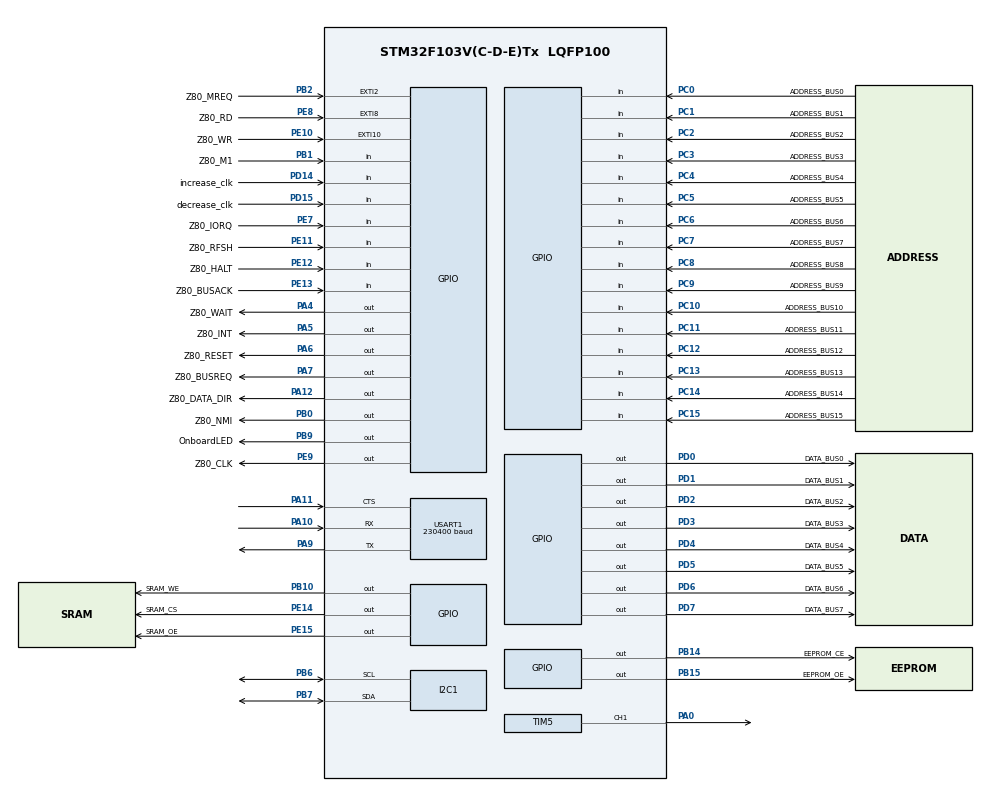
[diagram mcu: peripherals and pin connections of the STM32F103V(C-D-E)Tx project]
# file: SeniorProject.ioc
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Mcu.Family=STM32F1
Mcu.Name=STM32F103V(C-D-E)Tx
Mcu.Package=LQFP100
NVIC.EXTI15_10_IRQn=true\:0\:0\:false\:false\:true\:true
NVIC.EXTI2_IRQn=true\:0\:0\:false\:false\:true\:true
NVIC.EXTI9_5_IRQn=true\:0\:0\:false\:false\:true\:true
NVIC.PriorityGroup=NVIC_PRIORITYGROUP_4
PA0-WKUP.Signal=S_TIM5_CH1
PA10.Mode=Asynchronous
PA10.Signal=USART1_RX
PA11.Mode=CTS_Only
PA11.Signal=USART1_CTS
PA12.GPIO_Label=Z80_DATA_DIR
PA12.GPIO_Speed=GPIO_SPEED_FREQ_MEDIUM
PA12.PinState=GPIO_PIN_RESET
PA12.Signal=GPIO_Output
PA13.Mode=Serial_Wire
PA13.Signal=SYS_JTMS-SWDIO
PA14.Mode=Serial_Wire
PA14.Signal=SYS_JTCK-SWCLK
PA4.GPIO_Label=Z80_WAIT
PA4.GPIO_Speed=GPIO_SPEED_FREQ_MEDIUM
PA4.PinState=GPIO_PIN_SET
PA4.Signal=GPIO_Output
PA5.GPIO_Label=Z80_INT
PA5.GPIO_Speed=GPIO_SPEED_FREQ_MEDIUM
PA5.PinState=GPIO_PIN_SET
PA5.Signal=GPIO_Output
PA6.GPIO_Label=Z80_RESET
PA6.GPIO_Speed=GPIO_SPEED_FREQ_MEDIUM
PA6.PinState=GPIO_PIN_RESET
PA6.Signal=GPIO_Output
PA7.GPIO_Label=Z80_BUSREQ
PA7.GPIO_Speed=GPIO_SPEED_FREQ_MEDIUM
PA7.PinState=GPIO_PIN_SET
PA7.Signal=GPIO_Output
PA9.Mode=Asynchronous
PA9.Signal=USART1_TX
PB0.GPIO_Label=Z80_NMI
PB0.GPIO_Speed=GPIO_SPEED_FREQ_MEDIUM
PB0.Signal=GPIO_Output
PB1.GPIO_Label=Z80_M1
PB1.Signal=GPIO_Input
PB10.GPIO_Label=SRAM_WE
PB10.GPIO_Speed=GPIO_SPEED_FREQ_MEDIUM
PB10.PinState=GPIO_PIN_SET
PB10.Signal=GPIO_Output
PB14.GPIO_Label=EEPROM_CE
PB14.GPIO_Speed=GPIO_SPEED_FREQ_MEDIUM
PB14.PinState=GPIO_PIN_SET
PB14.Signal=GPIO_Output
PB15.GPIO_Label=EEPROM_OE
PB15.GPIO_Speed=GPIO_SPEED_FREQ_MEDIUM
PB15.PinState=GPIO_PIN_SET
PB15.Signal=GPIO_Output
PB2.GPIO_Label=Z80_MREQ
PB2.GPIO_ModeDefaultEXTI=GPIO_MODE_IT_FALLING
PB2.Signal=GPXTI2
PB6.Mode=I2C
PB6.Signal=I2C1_SCL
PB7.Mode=I2C
PB7.Signal=I2C1_SDA
PB9.GPIO_Label=OnboardLED
PB9.GPIO_ModeDefaultOutputPP=GPIO_MODE_OUTPUT_PP
PB9.PinState=GPIO_PIN_SET
PB9.Signal=GPIO_Output
PC0.GPIO_Label=ADDRESS_BUS0
PC0.Signal=GPIO_Input
PC1.GPIO_Label=ADDRESS_BUS1
PC1.Signal=GPIO_Input
PC10.GPIO_Label=ADDRESS_BUS10
PC10.Signal=GPIO_Input
PC11.GPIO_Label=ADDRESS_BUS11
PC11.Signal=GPIO_Input
PC12.GPIO_Label=ADDRESS_BUS12
PC12.Signal=GPIO_Input
PC13-TAMPER-RTC.GPIO_Label=ADDRESS_BUS13
PC13-TAMPER-RTC.Signal=GPIO_Input
PC14-OSC32_IN.GPIO_Label=ADDRESS_BUS14
PC14-OSC32_IN.Signal=GPIO_Input
PC15-OSC32_OUT.GPIO_Label=ADDRESS_BUS15
PC15-OSC32_OUT.Signal=GPIO_Input
PC2.GPIO_Label=ADDRESS_BUS2
PC2.Signal=GPIO_Input
PC3.GPIO_Label=ADDRESS_BUS3
PC3.Signal=GPIO_Input
PC4.GPIO_Label=ADDRESS_BUS4
PC4.Signal=GPIO_Input
PC5.GPIO_Label=ADDRESS_BUS5
PC5.Signal=GPIO_Input
PC6.GPIO_Label=ADDRESS_BUS6
PC6.Signal=GPIO_Input
PC7.GPIO_Label=ADDRESS_BUS7
PC7.Signal=GPIO_Input
PC8.GPIO_Label=ADDRESS_BUS8
PC8.Signal=GPIO_Input
PC9.GPIO_Label=ADDRESS_BUS9
PC9.Signal=GPIO_Input
PD0.GPIO_Label=DATA_BUS0
PD0.GPIO_Speed=GPIO_SPEED_FREQ_MEDIUM
PD0.Signal=GPIO_Output
PD1.GPIO_Label=DATA_BUS1
PD1.GPIO_Speed=GPIO_SPEED_FREQ_MEDIUM
PD1.Signal=GPIO_Output
PD14.GPIO_Label=increase_clk
PD14.Signal=GPIO_Input
PD15.GPIO_Label=decrease_clk
PD15.Signal=GPIO_Input
PD2.GPIO_Label=DATA_BUS2
PD2.GPIO_Speed=GPIO_SPEED_FREQ_MEDIUM
PD2.Signal=GPIO_Output
PD3.GPIO_Label=DATA_BUS3
PD3.GPIO_Speed=GPIO_SPEED_FREQ_MEDIUM
PD3.Signal=GPIO_Output
PD4.GPIO_Label=DATA_BUS4
PD4.GPIO_Speed=GPIO_SPEED_FREQ_MEDIUM
PD4.Signal=GPIO_Output
PD5.GPIO_Label=DATA_BUS5
PD5.GPIO_Speed=GPIO_SPEED_FREQ_MEDIUM
PD5.Signal=GPIO_Output
PD6.GPIO_Label=DATA_BUS6
PD6.GPIO_Speed=GPIO_SPEED_FREQ_MEDIUM
PD6.Signal=GPIO_Output
PD7.GPIO_Label=DATA_BUS7
PD7.GPIO_Speed=GPIO_SPEED_FREQ_MEDIUM
PD7.Signal=GPIO_Output
PE10.GPIO_Label=Z80_WR
PE10.GPIO_ModeDefaultEXTI=GPIO_MODE_IT_FALLING
PE10.Signal=GPXTI10
PE11.GPIO_Label=Z80_RFSH
PE11.Signal=GPIO_Input
PE12.GPIO_Label=Z80_HALT
PE12.Signal=GPIO_Input
PE13.GPIO_Label=Z80_BUSACK
PE13.Signal=GPIO_Input
PE14.GPIO_Label=SRAM_CS
PE14.GPIO_Speed=GPIO_SPEED_FREQ_MEDIUM
PE14.PinState=GPIO_PIN_SET
PE14.Signal=GPIO_Output
PE15.GPIO_Label=SRAM_OE
PE15.GPIO_Speed=GPIO_SPEED_FREQ_MEDIUM
PE15.PinState=GPIO_PIN_SET
PE15.Signal=GPIO_Output
PE7.GPIO_Label=Z80_IORQ
PE7.Signal=GPIO_Input
PE8.GPIO_Label=Z80_RD
PE8.GPIO_ModeDefaultEXTI=GPIO_MODE_IT_FALLING
PE8.Signal=GPXTI8
PE9.GPIO_Label=Z80_CLK
PE9.GPIO_Speed=GPIO_SPEED_FREQ_HIGH
PE9.Signal=GPIO_Output
ProjectManager.HeapSize=0x200
ProjectManager.StackSize=0x400
ProjectManager.TargetToolchain=SW4STM32
RCC.AHBFreq_Value=64000000
RCC.APB1CLKDivider=RCC_HCLK_DIV2
RCC.APB1Freq_Value=32000000
RCC.APB1TimFreq_Value=64000000
RCC.APB2Freq_Value=64000000
RCC.APB2TimFreq_Value=64000000
RCC.HCLKFreq_Value=64000000
RCC.PLLMUL=RCC_PLL_MUL16
RCC.SYSCLKFreq_VALUE=64000000
RCC.SYSCLKSource=RCC_SYSCLKSOURCE_PLLCLK
RCC.USBFreq_Value=64000000
SH.S_TIM5_CH1.0=TIM5_CH1,PWM Generation1 CH1
TIM5.Channel-PWM\ Generation1\ CH1=TIM_CHANNEL_1
TIM5.Period=2000
TIM5.Prescaler=8999
TIM5.Pulse-PWM\ Generation1\ CH1=1000
USART1.BaudRate=230400
USART1.VirtualMode=VM_ASYNC
VP_TIM5_VS_ClockSourceINT.Mode=Internal
board=SeniorProject

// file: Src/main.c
/**
  ******************************************************************************
  * File Name          : main.c
  * Description        : Main program body
  ******************************************************************************
  ** This notice applies to any and all portions of this file
  * that are not between comment pairs USER CODE BEGIN and
  * USER CODE END. Other portions of this file, whether
  * inserted by the user or by software development tools
  * are owned by their respective copyright owners.
  *
  * COPYRIGHT(c) 2017 STMicroelectronics
  *
  * Redistribution and use in source and binary forms, with or without modification,
  * are permitted provided that the following conditions are met:
  *   1. Redistributions of source code must retain the above copyright notice,
  *      this list of conditions and the following disclaimer.
  *   2. Redistributions in binary form must reproduce the above copyright notice,
  *      this list of conditions and the following disclaimer in the documentation
  *      and/or other materials provided with the distribution.
  *   3. Neither the name of STMicroelectronics nor the names of its contributors
  *      may be used to endorse or promote products derived from this software
  *      without specific prior written permission.
  *
  * THIS SOFTWARE IS PROVIDED BY THE COPYRIGHT HOLDERS AND CONTRIBUTORS "AS IS"
  * AND ANY EXPRESS OR IMPLIED WARRANTIES, INCLUDING, BUT NOT LIMITED TO, THE
  * IMPLIED WARRANTIES OF MERCHANTABILITY AND FITNESS FOR A PARTICULAR PURPOSE ARE
  * DISCLAIMED. IN NO EVENT SHALL THE COPYRIGHT HOLDER OR CONTRIBUTORS BE LIABLE
  * FOR ANY DIRECT, INDIRECT, INCIDENTAL, SPECIAL, EXEMPLARY, OR CONSEQUENTIAL
  * DAMAGES (INCLUDING, BUT NOT LIMITED TO, PROCUREMENT OF SUBSTITUTE GOODS OR
  * SERVICES; LOSS OF USE, DATA, OR PROFITS; OR BUSINESS INTERRUPTION) HOWEVER
  * CAUSED AND ON ANY THEORY OF LIABILITY, WHETHER IN CONTRACT, STRICT LIABILITY,
  * OR TORT (INCLUDING NEGLIGENCE OR OTHERWISE) ARISING IN ANY WAY OUT OF THE USE
  * OF THIS SOFTWARE, EVEN IF ADVISED OF THE POSSIBILITY OF SUCH DAMAGE.
  *
  ******************************************************************************
  */

#include "main.h"
#include "stm32f1xx_hal.h"
#include "i2c.h"
#include "tim.h"
#include "usart.h"
#include "gpio.h"

/* USER CODE BEGIN Includes */
#include "z80_functions.h"
#include "memory.h"
#include "custom_types.h"
#include "globals.h"
#include <stdio.h>
#include <stdlib.h>
#include <string.h>
/* USER CODE END Includes */

/* USER CODE BEGIN PV */
/* Private variables ---------------------------------------------------------*/

/* USER CODE END PV */

// test 1

void SystemClock_Config(void);

/* USER CODE BEGIN PFP */
/* Private function prototypes -----------------------------------------------*/

/* USER CODE END PFP */

int main(void)
{

  /* USER CODE BEGIN 1 */
	int m_z80_clk_freq = 10000;
	volatile uint16_t read_address;
	uint16_t write_address = 0;
	memory_map address_space;
	address_space.ROM.start = 0;
	address_space.ROM.stop = 32767;
	address_space.RAM.start = 32768;
	address_space.RAM.stop = 62335;
	address_space.display.start = 62336;
	address_space.display.stop = 65535;
	// Allocate memory for 80x40 character display
	char display_memory[40][80];

	//uint8_t program[] = {{0x00},{0x00},{0x00},{0x00},{0x00},{0x00},{0x00},{0x00}};
  /* USER CODE END 1 */

  /* MCU Configuration----------------------------------------------------------*/

  /* Reset of all peripherals, Initializes the Flash interface and the Systick. */
  HAL_Init();

  /* Configure the system clock */
  SystemClock_Config();

  /* Initialize all configured peripherals */
  MX_GPIO_Init();
  MX_I2C1_Init();
  MX_TIM5_Init();
  MX_USART1_UART_Init();

  /* USER CODE BEGIN 2 */
	/* Z80 Configuration----------------------------------------------------------*/

	init_z80_control_signals();
	init_z80_clk(m_z80_clk_freq);
	HAL_Delay(100);
	reset_z80();
  /* USER CODE END 2 */

  /* Infinite loop */
	while (1)
	{

	}
}

/** System Clock Configuration
*/
void SystemClock_Config(void)
{

  RCC_OscInitTypeDef RCC_OscInitStruct;
  RCC_ClkInitTypeDef RCC_ClkInitStruct;

    /**Initializes the CPU, AHB and APB busses clocks
    */
  RCC_OscInitStruct.OscillatorType = RCC_OSCILLATORTYPE_HSI;
  RCC_OscInitStruct.HSIState = RCC_HSI_ON;
  RCC_OscInitStruct.HSICalibrationValue = 16;
  RCC_OscInitStruct.PLL.PLLState = RCC_PLL_ON;
  RCC_OscInitStruct.PLL.PLLSource = RCC_PLLSOURCE_HSI_DIV2;
  RCC_OscInitStruct.PLL.PLLMUL = RCC_PLL_MUL16;
  if (HAL_RCC_OscConfig(&RCC_OscInitStruct) != HAL_OK)
  {
    _Error_Handler(__FILE__, __LINE__);
  }

    /**Initializes the CPU, AHB and APB busses clocks
    */
  RCC_ClkInitStruct.ClockType = RCC_CLOCKTYPE_HCLK|RCC_CLOCKTYPE_SYSCLK
                              |RCC_CLOCKTYPE_PCLK1|RCC_CLOCKTYPE_PCLK2;
  RCC_ClkInitStruct.SYSCLKSource = RCC_SYSCLKSOURCE_PLLCLK;
  RCC_ClkInitStruct.AHBCLKDivider = RCC_SYSCLK_DIV1;
  RCC_ClkInitStruct.APB1CLKDivider = RCC_HCLK_DIV2;
  RCC_ClkInitStruct.APB2CLKDivider = RCC_HCLK_DIV2;

  if (HAL_RCC_ClockConfig(&RCC_ClkInitStruct, FLASH_LATENCY_2) != HAL_OK)
  {
    _Error_Handler(__FILE__, __LINE__);
  }

    /**Configure the Systick interrupt time
    */
  HAL_SYSTICK_Config(HAL_RCC_GetHCLKFreq()/1000);

    /**Configure the Systick
    */
  HAL_SYSTICK_CLKSourceConfig(SYSTICK_CLKSOURCE_HCLK);

  /* SysTick_IRQn interrupt configuration */
  HAL_NVIC_SetPriority(SysTick_IRQn, 0, 0);
}

void _Error_Handler(char * file, int line)
{
  while(1)
  {
  }
}

/************************ (C) COPYRIGHT STMicroelectronics *****END OF FILE****/
